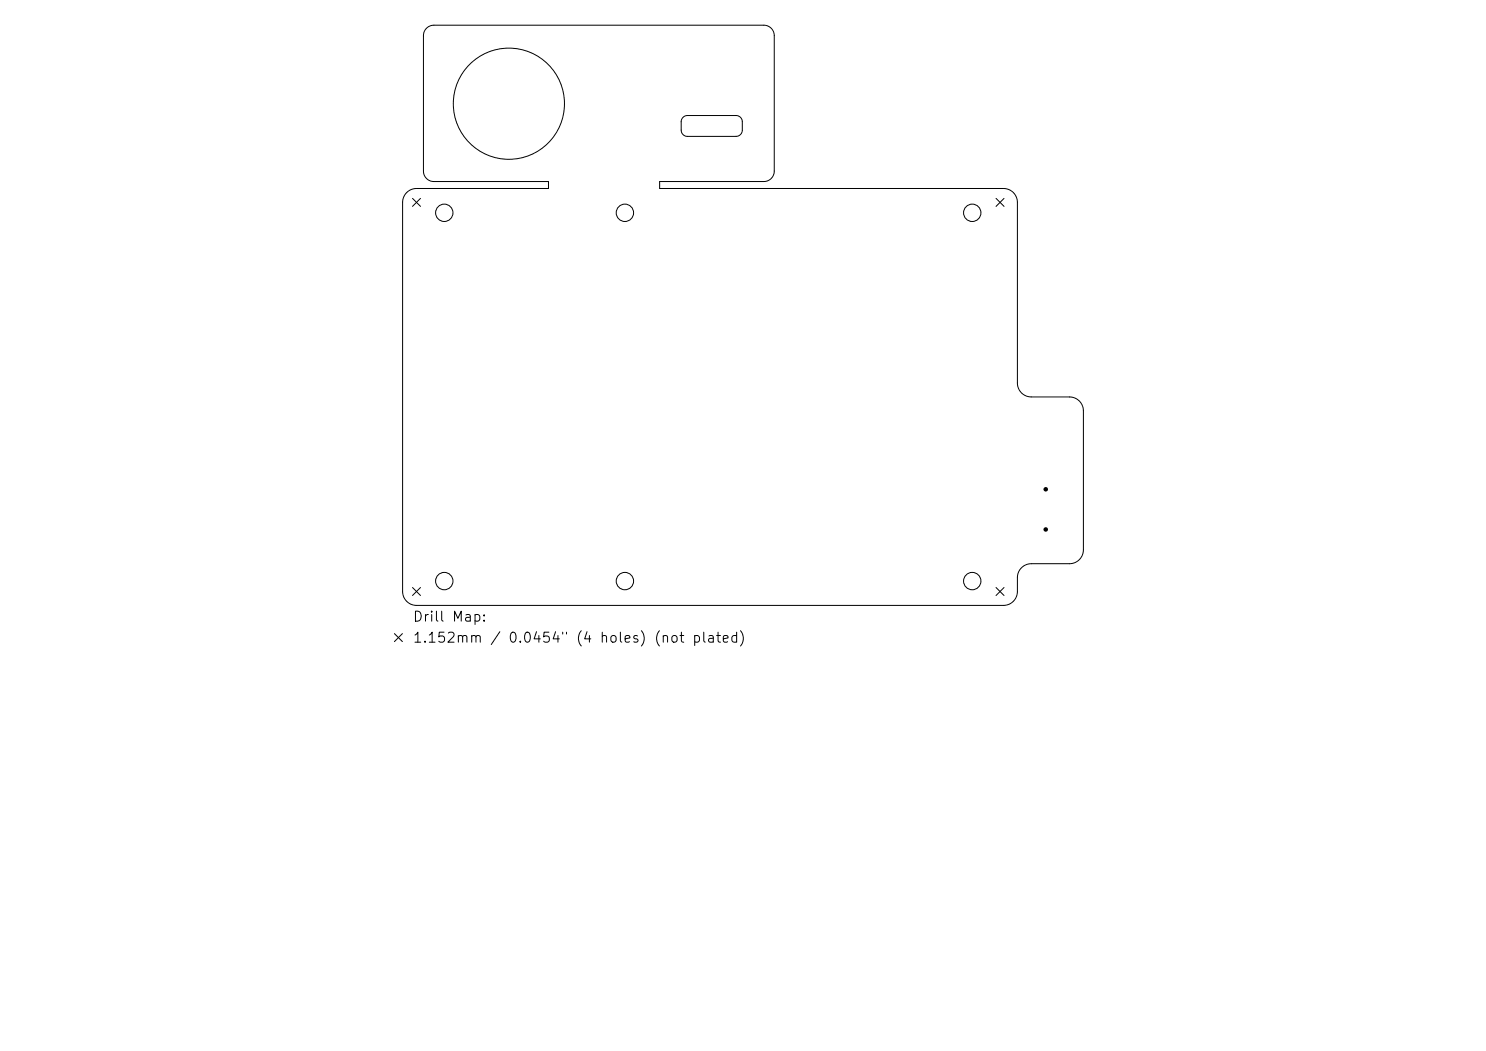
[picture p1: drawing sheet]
<svg xmlns="http://www.w3.org/2000/svg" width="297mm" height="210mm" viewBox="0 0 297 210" stroke-linecap="round" stroke-linejoin="round" font-family="sans-serif">
<defs><g id="words">
<g font-size="2">
<text x="82.4" y="124.7">Drill Map:</text>
<text x="82.4" y="128.9">1.152mm / 0.0454&quot; (4 holes) (not plated)</text>
</g>
</g></defs>
<g fill="none" stroke="#000" stroke-width=".2">
<path d="M85.2 5.6l.8-.4 .7-.2h66a2.08 2.08 0 0 1 2 2.1v27.1a2.08 2.08 0 0 1-2 2.1h-20.9v1.4h68.8a2.78 2.78 0 0 1 2.7 2.7v36.1a2.78 2.78 0 0 0 2.8 2.8h7.7a2.78 2.78 0 0 1 2.7 2.8v27.8a2.78 2.78 0 0 1-2.7 2.7h-7.7a2.78 2.78 0 0 0-2.8 2.8v2.8a2.78 2.78 0 0 1-2.7 2.8h-117.4a2.78 2.78 0 0 1-2.7-2.8v-77.8a2.78 2.78 0 0 1 2.7-2.7h26.4v-1.4h-22.9a2.08 2.08 0 0 1-2.1-2.1v-27.1l.2-.7zM82.4 39.6l1.6 1.6M84 39.6l-1.6 1.6M136.5 23.5l.9-.4h9.7a1.25 1.25 0 0 1 1.3 1.2v1.7a1.25 1.25 0 0 1-1.3 1.2h-9.7a1.25 1.25 0 0 1-1.3-1.2l.1-1.9zM199.1 39.6l1.6 1.6M200.7 39.6l-1.6 1.6M82.4 117.4l1.6 1.6M84 117.4l-1.6 1.6M199.1 117.4l1.6 1.6M200.7 117.4l-1.6 1.6M78.8 126.6l1.6 1.6M80.4 126.6l-1.6 1.6"/>
<circle cx="101.7" cy="20.7" r="11.1"/>
<circle cx="88.8" cy="42.5" r="1.74"/>
<circle cx="124.9" cy="42.5" r="1.74"/>
<circle cx="194.3" cy="42.5" r="1.74"/>
<circle cx="88.8" cy="116.1" r="1.74"/>
<circle cx="124.9" cy="116.1" r="1.74"/>
<circle cx="194.3" cy="116.1" r="1.74"/>
</g>
<g fill="#000">
<circle cx="209" cy="97.8" r=".45"/>
<circle cx="209" cy="105.8" r=".45"/>
</g>
<use href="#words"/>
</svg>
